VERSION 5.7 ;
  NOWIREEXTENSIONATPIN ON ;
  DIVIDERCHAR "/" ;
  BUSBITCHARS "[]" ;
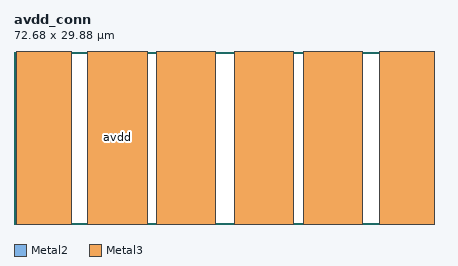
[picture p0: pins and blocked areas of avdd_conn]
MACRO avdd_conn
  CLASS BLOCK ;
  FOREIGN avdd_conn ;
  ORIGIN 0.000 0.000 ;
  SIZE 72.680 BY 29.880 ;
  PIN avdd
    DIRECTION INOUT ;
    USE POWER ;
    PORT
      LAYER Metal2 ;
        RECT 0.400 0.000 9.900 29.880 ;
        RECT 12.800 0.000 23.050 29.880 ;
        RECT 24.650 0.000 34.900 29.880 ;
        RECT 38.180 0.000 48.430 29.880 ;
        RECT 50.030 0.000 60.280 29.880 ;
        RECT 63.180 0.000 72.680 29.880 ;
      LAYER Metal3 ;
        RECT 0.400 0.000 9.900 29.880 ;
        RECT 12.800 0.000 23.050 29.880 ;
        RECT 24.650 0.000 34.900 29.880 ;
        RECT 38.180 0.000 48.430 29.880 ;
        RECT 50.030 0.000 60.280 29.880 ;
        RECT 63.180 0.000 72.680 29.880 ;
    END
  END avdd
END avdd_conn
END LIBRARY
